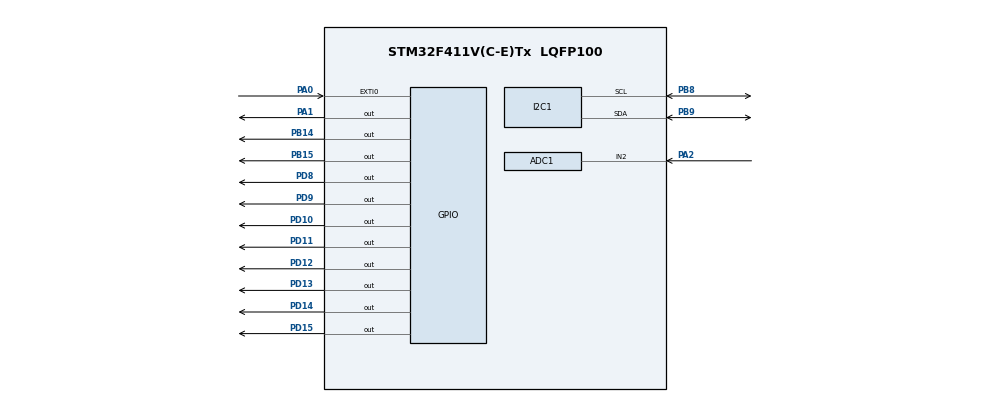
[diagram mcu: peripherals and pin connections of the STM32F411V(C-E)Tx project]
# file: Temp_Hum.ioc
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ADC1.Channel-0\#ChannelRegularConversion=ADC_CHANNEL_2
ADC1.NbrOfConversionFlag=1
ADC1.Rank-0\#ChannelRegularConversion=1
ADC1.SamplingTime-0\#ChannelRegularConversion=ADC_SAMPLETIME_3CYCLES
ADC1.master=1
Mcu.Family=STM32F4
Mcu.Name=STM32F411V(C-E)Tx
Mcu.Package=LQFP100
NVIC.PriorityGroup=NVIC_PRIORITYGROUP_0
PA0-WKUP.Signal=GPXTI0
PA1.Signal=GPIO_Output
PA2.Signal=ADCx_IN2
PB14.Signal=GPIO_Output
PB15.Signal=GPIO_Output
PB8.Mode=I2C
PB8.Signal=I2C1_SCL
PB9.Mode=I2C
PB9.Signal=I2C1_SDA
PD10.Signal=GPIO_Output
PD11.Signal=GPIO_Output
PD12.Signal=GPIO_Output
PD13.Signal=GPIO_Output
PD14.Signal=GPIO_Output
PD15.Signal=GPIO_Output
PD8.Signal=GPIO_Output
PD9.Signal=GPIO_Output
ProjectManager.HeapSize=0x200
ProjectManager.StackSize=0x400
ProjectManager.TargetToolchain=STM32CubeIDE
RCC.48MHZClocksFreq_Value=12500000
RCC.AHBFreq_Value=50000000
RCC.APB1CLKDivider=RCC_HCLK_DIV4
RCC.APB1Freq_Value=12500000
RCC.APB1TimFreq_Value=25000000
RCC.APB2Freq_Value=50000000
RCC.APB2TimFreq_Value=50000000
RCC.CortexFreq_Value=50000000
RCC.HCLKFreq_Value=50000000
RCC.HSE_VALUE=8000000
RCC.HSI_VALUE=16000000
RCC.PLLI2SM=5
RCC.PLLI2SN=200
RCC.PLLM=8
RCC.PLLN=50
RCC.PLLQ=8
RCC.SYSCLKFreq_VALUE=50000000
RCC.SYSCLKSource=RCC_SYSCLKSOURCE_PLLCLK
RCC.VCOOutputFreq_Value=100000000
SH.ADCx_IN2.0=ADC1_IN2,IN2
TIM2.Period=5000
TIM2.Prescaler=50000
VP_TIM2_VS_ClockSourceINT.Mode=Internal
board=STM32F411E-DISCO

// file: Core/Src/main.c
/* USER CODE BEGIN Header */
/**
  ******************************************************************************
  * @file           : main.c
  * @brief          : Main program body
  ******************************************************************************
  * @attention
  *
  * Copyright (c) 2024 STMicroelectronics.
  * All rights reserved.
  *
  * This software is licensed under terms that can be found in the LICENSE file
  * in the root directory of this software component.
  * If no LICENSE file comes with this software, it is provided AS-IS.
  *
  ******************************************************************************
  */
/* USER CODE END Header */
#include "main.h"

/* USER CODE BEGIN Includes */

#include "i2c-lcd.h"
#include "DHT.h"
#include "math.h"

#define NUMERO_LED 10

typedef struct PINES{
	GPIO_TypeDef *GPIOx;
	uint16_t GPIO_Pin;
}PINES;

/* USER CODE END Includes */

ADC_HandleTypeDef hadc1;

I2C_HandleTypeDef hi2c1;

TIM_HandleTypeDef htim2;

void SystemClock_Config(void);
static void MX_GPIO_Init(void);
static void MX_I2C1_Init(void);
static void MX_ADC1_Init(void);
static void MX_TIM2_Init(void);

/* USER CODE BEGIN 0 */

//variables globales:
PINES PINES_LED[] = {{GPIOB,GPIO_PIN_14},{GPIOB,GPIO_PIN_15},{GPIOD,GPIO_PIN_8},
						 {GPIOD,GPIO_PIN_9},{GPIOD,GPIO_PIN_10},{GPIOD,GPIO_PIN_11},
						 {GPIOD,GPIO_PIN_12},{GPIOD,GPIO_PIN_13},{GPIOD,GPIO_PIN_14},
						 {GPIOD,GPIO_PIN_15}};
DHT_DataTypedef DHT11_Data; //Estructura para guardar la temperatura y humedad
float Humedad; //Variable para guardar la humedad
float Temperatura; //Variable para guardar la temperatura
volatile int Seleccion_estado = 0; //Se emplea para cambiar el estado y seleccionar la temperatura que queremos
								   //Se pone como volatile pues se usa como interrupción
static float Temp_control = 25.0; //Temperatura que queremos mantener. Se inicializa en 25ºC
uint16_t Lec_Temp_Control; //Guarda el valor de la lectura analógica del potenciómetro usado para establecer la Temperatura de control
						   //Se ha usado una resolución de 8 bits para el ADC
static uint8_t T_min = 15 , T_max = 40 ; //Se definen unos márgenes de funcionamiento que se pueden cambiar
uint8_t T_diff = 0; ; //Diferencia entre los márgenes de temperatura. Se emplea para la interpolación del potenciómetro

//prototipo de funciones utilizadas
//Nos devuelve TRUE cuando se presiona el boton tras el periodo de debounce
int debouncer(volatile int* button_int, GPIO_TypeDef* GPIO_port, uint16_t GPIO_number);

// Se encienden los LEDs correspondientes a la temperatura seleccionada y apaga los demas */
void encenderled(int i, PINES PINES_LED[]);

//INTERRUPCIONES

void HAL_GPIO_EXTI_Callback(uint16_t GPIO_Pin) // Cuando se pulsa el boton azul de la placa (User Button PA0), se genera la interrupción
{
	//Interrupcion debida al PIN_0
	if(GPIO_Pin==GPIO_PIN_0)
	{
		Seleccion_estado = 1;
	}
}

void HAL_TIM_PeriodElapsedCallback(TIM_HandleTypeDef *htim) // Genera una interrupción cada 5 segundos
{
  /* Prevent unused argument(s) compilation warning */
  UNUSED(htim);
  /* NOTE : This function Should not be modified, when the callback is needed,
            the __HAL_TIM_PeriodElapsedCallback could be implemented in the user file */
  //Obtencion de datos del sensor (observar la librería "DHT22.h")
	  DHT_GetData(&DHT11_Data);

  //Asignación de variables globales de Temperatura y Humedad
      Temperatura = DHT11_Data.Temperatura;
	  Humedad = DHT11_Data.Humedad;
	}

/* USER CODE END 0 */

int main(void)
{
  /* USER CODE BEGIN 1 */

//Asignación de variables
	T_diff = T_max - T_min;
	float salto_temp = T_diff / NUMERO_LED; //Empleado en el cambio en los LEDs iluminados
	int total_led = 0; //numero total de LEDs que se tienen que encender
	int j = 1; //para usarlo en un bucle

//Variables locales
	//uint32_t tick_start; //guardará ek valor de HAL_GetTick()
	//int t_espera = 2000; //el tiempo de espera en milisegundos (ms)

	/* USER CODE END 1 */

  /* MCU Configuration--------------------------------------------------------*/

  /* Reset of all peripherals, Initializes the Flash interface and the Systick. */
  HAL_Init();

  /* Configure the system clock */
  SystemClock_Config();

  /* Initialize all configured peripherals */
  MX_GPIO_Init();
  MX_I2C1_Init();
  MX_ADC1_Init();
  MX_TIM2_Init();
  /* USER CODE BEGIN 2 */

  //Mensaje que aparece al principio:

  lcd_init();
  lcd_clear();
  lcd_put_cur(0,0);
  lcd_send_string("EMPEZANDO--->");
  HAL_Delay(2000);
  lcd_clear();

  //Habilitamos las interrupciones
  HAL_NVIC_EnableIRQ(EXTI0_IRQn);
  HAL_TIM_Base_Start_IT(&htim2);

  //Habilitamos el ADC (Analogic Digital Conversor)
  HAL_ADC_Start(&hadc1);

  /* USER CODE END 2 */

  /* Infinite loop */
  while (1)
  {

    /* USER CODE BEGIN 3 */

	 if(debouncer(&Seleccion_estado, GPIOA, GPIO_PIN_0)) //Estado de seleccion de temperatura de control
	 {
		 lcd_clear();
		 lcd_put_cur(0,0);
		 lcd_send_string("Elija nueva Temp");
		 int i = 1;

		 while(!debouncer(&Seleccion_estado,GPIOA, GPIO_PIN_0))
		 {
			 //Habilitacion del ADC
			 HAL_ADC_Start(&hadc1);

			 //Lectura del ADC
			 if(HAL_ADC_PollForConversion(&hadc1, HAL_MAX_DELAY) == HAL_OK)
				 Lec_Temp_Control = HAL_ADC_GetValue(&hadc1);

			 //Asignacion de la temperatura de control
			 Temp_control = (float)Lec_Temp_Control / 255 * T_diff + 15; //pendiente de interpolación = 25/255

			 //Se muestra en pantalla la temperatura escogida. Para evitar el parpadeo y reducir la frecuencia de la pantalla se añade el bucle
			 if (!(i++ % 20000))
			 {
				 Display_Temp(Temp_control*10 , 1);
				 i = 1;
			 }
		 }

		 //Desabilitacion del ADC
		 HAL_ADC_Stop(&hadc1);

	 }

	 else //estado para ejecutar el programa con una temperatura de control dada
	 {
		 //se muestran los valores obtenidos en el LCD (observar la libreria "i2c-lcd.h")
		 if (!(j++ % 20000))
		 {
			 Display_HR(Humedad);
			 Display_Temp(Temperatura , 0);
			 j = 1;
		 }

		 //Control de la barra LED. Truncamos el numero de LED dependiendo del salto térmico
		 total_led = (int)((Temperatura/10 - T_min) / salto_temp);
		 encenderled(total_led,PINES_LED);

	 }
  }
  /* USER CODE END 3 */
}

void SystemClock_Config(void)
{
  RCC_OscInitTypeDef RCC_OscInitStruct = {0};
  RCC_ClkInitTypeDef RCC_ClkInitStruct = {0};

  /** Configure the main internal regulator output voltage
  */
  __HAL_RCC_PWR_CLK_ENABLE();
  __HAL_PWR_VOLTAGESCALING_CONFIG(PWR_REGULATOR_VOLTAGE_SCALE1);

  /** Initializes the RCC Oscillators according to the specified parameters
  * in the RCC_OscInitTypeDef structure.
  */
  RCC_OscInitStruct.OscillatorType = RCC_OSCILLATORTYPE_HSI;
  RCC_OscInitStruct.HSIState = RCC_HSI_ON;
  RCC_OscInitStruct.HSICalibrationValue = RCC_HSICALIBRATION_DEFAULT;
  RCC_OscInitStruct.PLL.PLLState = RCC_PLL_ON;
  RCC_OscInitStruct.PLL.PLLSource = RCC_PLLSOURCE_HSI;
  RCC_OscInitStruct.PLL.PLLM = 8;
  RCC_OscInitStruct.PLL.PLLN = 50;
  RCC_OscInitStruct.PLL.PLLP = RCC_PLLP_DIV2;
  RCC_OscInitStruct.PLL.PLLQ = 8;
  if (HAL_RCC_OscConfig(&RCC_OscInitStruct) != HAL_OK)
  {
    Error_Handler();
  }

  /** Initializes the CPU, AHB and APB buses clocks
  */
  RCC_ClkInitStruct.ClockType = RCC_CLOCKTYPE_HCLK|RCC_CLOCKTYPE_SYSCLK
                              |RCC_CLOCKTYPE_PCLK1|RCC_CLOCKTYPE_PCLK2;
  RCC_ClkInitStruct.SYSCLKSource = RCC_SYSCLKSOURCE_PLLCLK;
  RCC_ClkInitStruct.AHBCLKDivider = RCC_SYSCLK_DIV1;
  RCC_ClkInitStruct.APB1CLKDivider = RCC_HCLK_DIV1;
  RCC_ClkInitStruct.APB2CLKDivider = RCC_HCLK_DIV1;

  if (HAL_RCC_ClockConfig(&RCC_ClkInitStruct, FLASH_LATENCY_1) != HAL_OK)
  {
    Error_Handler();
  }
}

static void MX_ADC1_Init(void)
{

  ADC_ChannelConfTypeDef sConfig = {0};

  /** Configure the global features of the ADC (Clock, Resolution, Data Alignment and number of conversion)
  */
  hadc1.Instance = ADC1;
  hadc1.Init.ClockPrescaler = ADC_CLOCK_SYNC_PCLK_DIV2;
  hadc1.Init.Resolution = ADC_RESOLUTION_8B;
  hadc1.Init.ScanConvMode = DISABLE;
  hadc1.Init.ContinuousConvMode = DISABLE;
  hadc1.Init.DiscontinuousConvMode = DISABLE;
  hadc1.Init.ExternalTrigConvEdge = ADC_EXTERNALTRIGCONVEDGE_NONE;
  hadc1.Init.ExternalTrigConv = ADC_SOFTWARE_START;
  hadc1.Init.DataAlign = ADC_DATAALIGN_RIGHT;
  hadc1.Init.NbrOfConversion = 1;
  hadc1.Init.DMAContinuousRequests = DISABLE;
  hadc1.Init.EOCSelection = ADC_EOC_SINGLE_CONV;
  if (HAL_ADC_Init(&hadc1) != HAL_OK)
  {
    Error_Handler();
  }

  /** Configure for the selected ADC regular channel its corresponding rank in the sequencer and its sample time.
  */
  sConfig.Channel = ADC_CHANNEL_2;
  sConfig.Rank = 1;
  sConfig.SamplingTime = ADC_SAMPLETIME_3CYCLES;
  if (HAL_ADC_ConfigChannel(&hadc1, &sConfig) != HAL_OK)
  {
    Error_Handler();
  }

}

static void MX_I2C1_Init(void)
{

  hi2c1.Instance = I2C1;
  hi2c1.Init.ClockSpeed = 100000;
  hi2c1.Init.DutyCycle = I2C_DUTYCYCLE_2;
  hi2c1.Init.OwnAddress1 = 0;
  hi2c1.Init.AddressingMode = I2C_ADDRESSINGMODE_7BIT;
  hi2c1.Init.DualAddressMode = I2C_DUALADDRESS_DISABLE;
  hi2c1.Init.OwnAddress2 = 0;
  hi2c1.Init.GeneralCallMode = I2C_GENERALCALL_DISABLE;
  hi2c1.Init.NoStretchMode = I2C_NOSTRETCH_DISABLE;
  if (HAL_I2C_Init(&hi2c1) != HAL_OK)
  {
    Error_Handler();
  }

}

static void MX_TIM2_Init(void)
{

  TIM_ClockConfigTypeDef sClockSourceConfig = {0};
  TIM_MasterConfigTypeDef sMasterConfig = {0};

  htim2.Instance = TIM2;
  htim2.Init.Prescaler = 50000;
  htim2.Init.CounterMode = TIM_COUNTERMODE_UP;
  htim2.Init.Period = 5000;
  htim2.Init.ClockDivision = TIM_CLOCKDIVISION_DIV1;
  htim2.Init.AutoReloadPreload = TIM_AUTORELOAD_PRELOAD_DISABLE;
  if (HAL_TIM_Base_Init(&htim2) != HAL_OK)
  {
    Error_Handler();
  }
  sClockSourceConfig.ClockSource = TIM_CLOCKSOURCE_INTERNAL;
  if (HAL_TIM_ConfigClockSource(&htim2, &sClockSourceConfig) != HAL_OK)
  {
    Error_Handler();
  }
  sMasterConfig.MasterOutputTrigger = TIM_TRGO_RESET;
  sMasterConfig.MasterSlaveMode = TIM_MASTERSLAVEMODE_DISABLE;
  if (HAL_TIMEx_MasterConfigSynchronization(&htim2, &sMasterConfig) != HAL_OK)
  {
    Error_Handler();
  }

}

static void MX_GPIO_Init(void)
{
  GPIO_InitTypeDef GPIO_InitStruct = {0};

  /* GPIO Ports Clock Enable */
  __HAL_RCC_GPIOA_CLK_ENABLE();
  __HAL_RCC_GPIOB_CLK_ENABLE();
  __HAL_RCC_GPIOD_CLK_ENABLE();

  /*Configure GPIO pin Output Level */
  HAL_GPIO_WritePin(GPIOA, GPIO_PIN_1, GPIO_PIN_RESET);

  /*Configure GPIO pin Output Level */
  HAL_GPIO_WritePin(GPIOB, GPIO_PIN_14|GPIO_PIN_15, GPIO_PIN_RESET);

  /*Configure GPIO pin Output Level */
  HAL_GPIO_WritePin(GPIOD, GPIO_PIN_8|GPIO_PIN_9|GPIO_PIN_10|GPIO_PIN_11
                          |GPIO_PIN_12|GPIO_PIN_13|GPIO_PIN_14|GPIO_PIN_15, GPIO_PIN_RESET);

  /*Configure GPIO pin : PA0 */
  GPIO_InitStruct.Pin = GPIO_PIN_0;
  GPIO_InitStruct.Mode = GPIO_MODE_IT_RISING;
  GPIO_InitStruct.Pull = GPIO_NOPULL;
  HAL_GPIO_Init(GPIOA, &GPIO_InitStruct);

  /*Configure GPIO pin : PA1 */
  GPIO_InitStruct.Pin = GPIO_PIN_1;
  GPIO_InitStruct.Mode = GPIO_MODE_OUTPUT_PP;
  GPIO_InitStruct.Pull = GPIO_NOPULL;
  GPIO_InitStruct.Speed = GPIO_SPEED_FREQ_LOW;
  HAL_GPIO_Init(GPIOA, &GPIO_InitStruct);

  /*Configure GPIO pins : PB14 PB15 */
  GPIO_InitStruct.Pin = GPIO_PIN_14|GPIO_PIN_15;
  GPIO_InitStruct.Mode = GPIO_MODE_OUTPUT_PP;
  GPIO_InitStruct.Pull = GPIO_NOPULL;
  GPIO_InitStruct.Speed = GPIO_SPEED_FREQ_LOW;
  HAL_GPIO_Init(GPIOB, &GPIO_InitStruct);

  /*Configure GPIO pins : PD8 PD9 PD10 PD11
                           PD12 PD13 PD14 PD15 */
  GPIO_InitStruct.Pin = GPIO_PIN_8|GPIO_PIN_9|GPIO_PIN_10|GPIO_PIN_11
                          |GPIO_PIN_12|GPIO_PIN_13|GPIO_PIN_14|GPIO_PIN_15;
  GPIO_InitStruct.Mode = GPIO_MODE_OUTPUT_PP;
  GPIO_InitStruct.Pull = GPIO_NOPULL;
  GPIO_InitStruct.Speed = GPIO_SPEED_FREQ_LOW;
  HAL_GPIO_Init(GPIOD, &GPIO_InitStruct);

  //EXTI interrupt init
  HAL_NVIC_SetPriority(EXTI0_IRQn, 0, 0);
  HAL_NVIC_EnableIRQ(EXTI0_IRQn);

}

/* USER CODE BEGIN 4 */

//Definicion de las funciones empleadas:
int debouncer(volatile int* button_int, GPIO_TypeDef* GPIO_port, uint16_t GPIO_number)
{
	static uint8_t button_count = 0;
	static int counter = 0;

	if (*button_int==1)
	{
		if (button_count==0)
		{
			counter=HAL_GetTick();
			button_count++;
		}
		if (HAL_GetTick()-counter>=20)
		{
			counter = HAL_GetTick();
			if (HAL_GPIO_ReadPin(GPIO_port, GPIO_number)!=1)
			{
				button_count=1;
			}
			else
			{
				button_count++;
			}
			if (button_count==4) //periodo antirrebotes
			{
				button_count=0;
				*button_int=0;
				return 1;
			}
		}

	}
	return 0;
}

void encenderled (int i, PINES PINES_LED[])
{
	int j = 0;

	for (int n=0; n<i; n++)
	{
		HAL_GPIO_WritePin(PINES_LED[n].GPIOx, PINES_LED[n].GPIO_Pin, GPIO_PIN_SET);
		j++;
	}

	while(j < NUMERO_LED)
	{
		HAL_GPIO_WritePin(PINES_LED[j].GPIOx, PINES_LED[j].GPIO_Pin, GPIO_PIN_RESET);
		j++;
	}
}
/* USER CODE END 4 */

void Error_Handler(void)
{
  __disable_irq();
  while (1)
  {
  }
}
